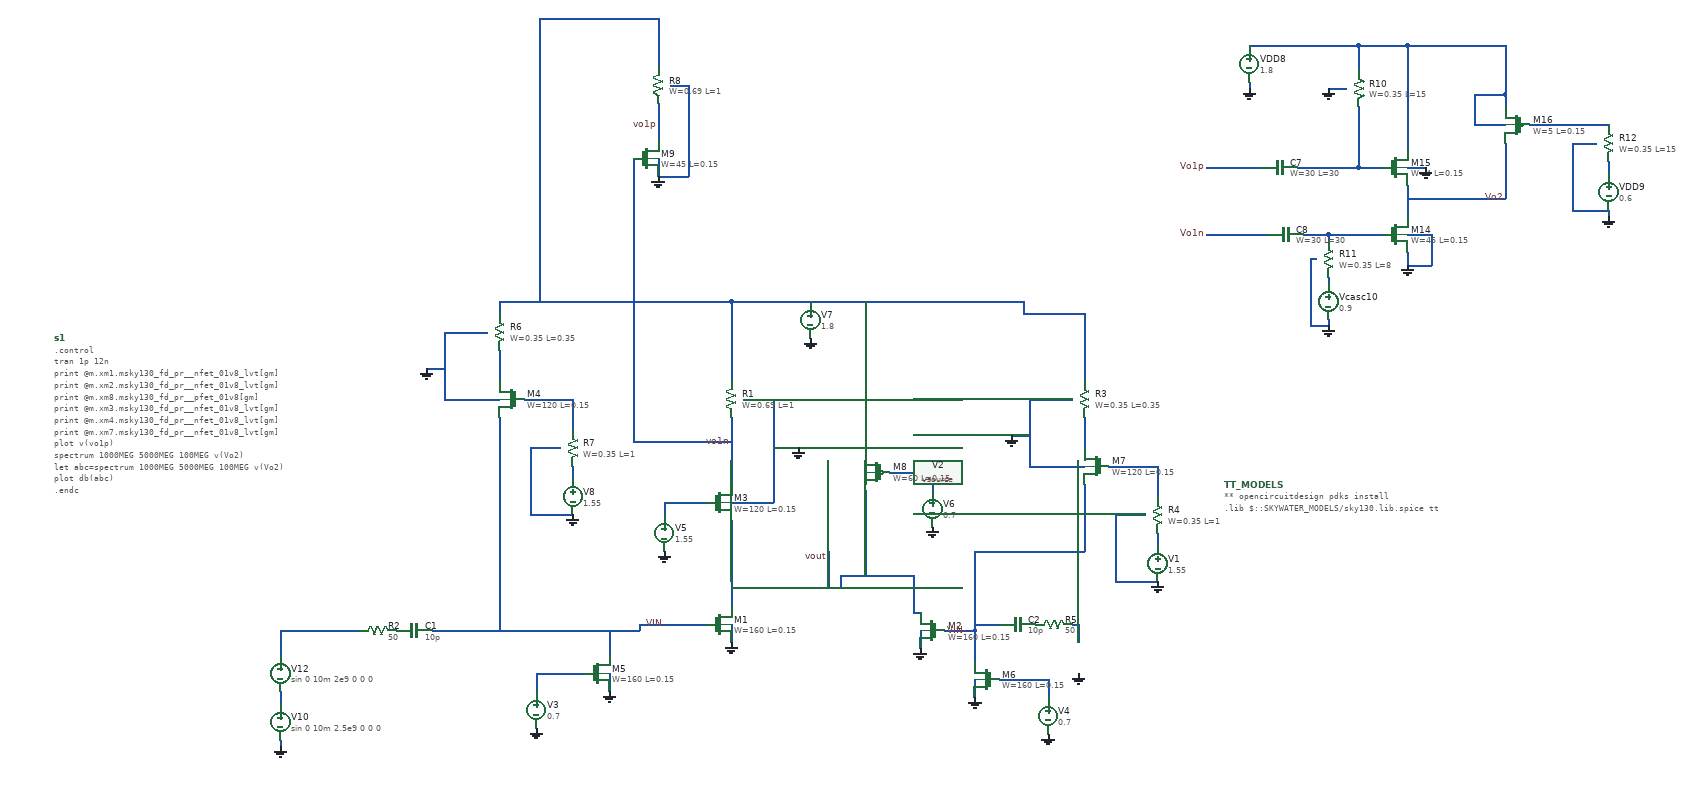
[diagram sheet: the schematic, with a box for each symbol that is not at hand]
v {xschem version=3.0.0 file_version=1.2 }
G {}
K {}
V {}
S {}
E {}
N 90 -90 90 -40 {
lab=vout}
N 390 -90 390 -30 {
lab=vout}
N 390 -30 400 -30 {
lab=vout}
N -10 -10 50 -10 {
lab=VIN}
N 490 0 490 20 {
lab=VIN-}
N 440 -0 490 0 {
lab=VIN-}
N -60 -10 -10 -10 {
lab=VIN}
N 490 -10 530 -10 {
lab=VIN-}
N 490 -10 490 0 {
lab=VIN-}
N -650 0 -650 40 {
lab=#net1}
N 660 -10 660 20 {
lab=#net2}
N -230 70 -230 100 {
lab=#net3}
N 400 0 400 30 {
lab=GND}
N 90 -10 90 20 {
lab=GND}
N 270 -90 390 -90 {
lab=vout}
N 270 -90 270 -70 {
lab=vout}
N 90 -70 270 -70 {
lab=vout}
N -650 100 -650 120 {
lab=#net4}
N -650 180 -650 190 {
lab=GND}
N -650 0 -520 0 {
lab=#net1}
N 250 -130 250 -70 {
lab=vout}
N 650 -10 660 -10 {
lab=#net2}
N 90 -180 90 -80 {
lab=vout}
N -20 -210 50 -210 {
lab=#net5}
N -20 -210 -20 -190 {
lab=#net5}
N 110 -380 160 -380 {
lab=GND}
N 160 -380 160 -220 {
lab=GND}
N 160 -220 160 -210 {
lab=GND}
N 90 -210 160 -210 {
lab=GND}
N 90 -350 90 -240 {
lab=vo1n}
N 90 -540 220 -540 {
lab=#net6}
N 90 -540 90 -410 {
lab=#net6}
N 160 -300 200 -300 {
lab=GND}
N -400 0 -60 0 {
lab=VIN}
N -60 -10 -60 0 {
lab=VIN}
N -290 -350 -290 0 {
lab=VIN}
N -290 -540 90 -540 {
lab=#net6}
N -290 -540 -290 -520 {
lab=#net6}
N -290 -460 -290 -400 {
lab=#net7}
N -380 -490 -310 -490 {
lab=GND}
N -380 -490 -380 -380 {
lab=GND}
N -380 -380 -290 -380 {
lab=GND}
N -410 -430 -380 -430 {
lab=GND}
N -170 -270 -170 -250 {
lab=#net8}
N -170 -380 -170 -330 {
lab=#net9}
N -250 -380 -170 -380 {
lab=#net9}
N -240 -300 -190 -300 {
lab=GND}
N -240 -300 -240 -190 {
lab=GND}
N -240 -190 -170 -190 {
lab=GND}
N -230 70 -150 70 {
lab=#net3}
N -110 10 -110 40 {
lab=VIN}
N -110 0 -110 20 {
lab=VIN}
N -110 70 -110 100 {
lab=GND}
N 610 80 610 110 {
lab=#net10}
N 530 80 610 80 {
lab=#net10}
N 490 80 490 110 {
lab=GND}
N 490 20 490 50 {
lab=VIN-}
N 220 -540 490 -540 {
lab=#net6}
N 310 -230 310 -90 {
lab=vout}
N 310 -530 310 -290 {
lab=#net6}
N 310 -540 310 -530 {
lab=#net6}
N 310 -290 310 -260 {
lab=#net6}
N 420 -260 420 -230 {
lab=#net11}
N 350 -260 420 -260 {
lab=#net11}
N -70 -310 90 -310 {
lab=vo1n}
N -70 -415 -70 -310 {
lab=vo1n}
N -70 -775 -70 -475 {
lab=vo1n}
N -10 -895 20 -895 {
lab=GND}
N 20 -895 20 -755 {
lab=GND}
N 20 -755 20 -745 {
lab=GND}
N -30 -745 20 -745 {
lab=GND}
N -30 -865 -30 -805 {
lab=vo1p}
N -30 -1005 -30 -925 {
lab=#net6}
N -30 -775 -30 -745 {
lab=GND}
N -225 -1000 -225 -540 {
lab=#net6}
N -225 -1005 -30 -1005 {
lab=#net6}
N -225 -1005 -225 -995 {
lab=#net6}
N -70 -480 -70 -410 {
lab=vo1n}
N 670 -430 670 -410 {
lab=#net6}
N 670 -350 670 -290 {
lab=#net12}
N 580 -380 650 -380 {
lab=GND}
N 580 -380 580 -270 {
lab=GND}
N 580 -270 670 -270 {
lab=GND}
N 550 -320 580 -320 {
lab=GND}
N 790 -160 790 -140 {
lab=#net13}
N 790 -270 790 -220 {
lab=#net14}
N 710 -270 790 -270 {
lab=#net14}
N 720 -190 770 -190 {
lab=GND}
N 720 -190 720 -80 {
lab=GND}
N 720 -80 790 -80 {
lab=GND}
N 670 -520 670 -430 {
lab=#net6}
N 670 -240 670 -130 {
lab=VIN-}
N 490 -130 670 -130 {
lab=VIN-}
N 490 -130 490 0 {
lab=VIN-}
N 490 -540 570 -540 {
lab=#net6}
N 570 -540 570 -520 {
lab=#net6}
N 570 -520 670 -520 {
lab=#net6}
N 1070 -890 1100 -890 { lab=GND}
N 1120 -760 1160 -760 { lab=#net15}
N 1120 -860 1120 -760 { lab=#net15}
N 1200 -960 1200 -790 { lab=#net16}
N 1120 -960 1200 -960 { lab=#net16}
N 1120 -960 1120 -920 { lab=#net16}
N 1200 -730 1200 -680 { lab=Vo2}
N 1200 -760 1230 -760 { lab=GND}
N 1360 -800 1360 -710 { lab=Vo2}
N 1200 -710 1360 -710 { lab=Vo2}
N 1310 -830 1360 -830 { lab=#net16}
N 1310 -880 1310 -830 { lab=#net16}
N 1310 -880 1360 -880 { lab=#net16}
N 1360 -880 1360 -860 { lab=#net16}
N 1360 -960 1360 -880 { lab=#net16}
N 1200 -960 1360 -960 { lab=#net16}
N 1400 -830 1430 -830 { lab=#net17}
N 940 -900 940 -890 { lab=GND}
N 940 -960 1120 -960 { lab=#net16}
N 1530 -690 1530 -680 { lab=GND}
N 1420 -830 1470 -830 { lab=#net17}
N 1200 -650 1240 -650 { lab=GND}
N 1240 -650 1240 -600 { lab=GND}
N 1200 -600 1240 -600 { lab=GND}
N 1200 -620 1200 -600 { lab=GND}
N 1020 -760 1120 -760 { lab=#net15}
N 870 -760 960 -760 { lab=Vo1p}
N 1070 -510 1070 -500 { lab=GND}
N 1070 -580 1070 -570 { lab=#net18}
N 1040 -610 1050 -610 { lab=GND}
N 1040 -610 1040 -500 { lab=GND}
N 1040 -500 1070 -500 { lab=GND}
N 1070 -650 1070 -640 { lab=#net19}
N 1070 -650 1160 -650 { lab=#net19}
N 1030 -650 1070 -650 { lab=#net19}
N 870 -650 970 -650 { lab=Vo1n}
N 1470 -830 1530 -830 { lab=#net17}
N 1530 -770 1530 -750 { lab=#net20}
N 1470 -800 1510 -800 { lab=GND}
N 1470 -800 1470 -700 { lab=GND}
N 1470 -700 1470 -690 { lab=GND}
N 1470 -690 1530 -690 { lab=GND}
C {sky130_fd_pr/nfet_01v8_lvt.sym} 70 -10 0 0 {name=M1
L=0.15
W=160
nf=20
mult=1
ad="'int((nf+1)/2) * W/nf * 0.29'" 
pd="'2*int((nf+1)/2) * (W/nf + 0.29)'"
as="'int((nf+2)/2) * W/nf * 0.29'" 
ps="'2*int((nf+2)/2) * (W/nf + 0.29)'"
nrd="'0.29 / W'" nrs="'0.29 / W'"
sa=0 sb=0 sd=0
model=nfet_01v8_lvt
spiceprefix=X
}
C {sky130_fd_pr/nfet_01v8_lvt.sym} 420 0 0 1 {name=M2
L=0.15
W=160
nf=20
mult=1
ad="'int((nf+1)/2) * W/nf * 0.29'" 
pd="'2*int((nf+1)/2) * (W/nf + 0.29)'"
as="'int((nf+2)/2) * W/nf * 0.29'" 
ps="'2*int((nf+2)/2) * (W/nf + 0.29)'"
nrd="'0.29 / W'" nrs="'0.29 / W'"
sa=0 sb=0 sd=0
model=nfet_01v8_lvt
spiceprefix=X
}
C {devices/capa.sym} -430 0 3 0 {name=C1
m=1
value=10p
footprint=1206
device="ceramic capacitor"}
C {devices/capa.sym} 560 -10 1 0 {name=C2
m=1
value=10p
footprint=1206
device="ceramic capacitor"}
C {devices/vsource.sym} 660 40 0 0 {name=V2 value="sin 0 10m 2.5e9 0 0 180"}
C {devices/gnd.sym} 90 20 0 0 {name=l2 lab=GND}
C {devices/gnd.sym} 400 30 0 0 {name=l3 lab=GND}
C {devices/gnd.sym} 660 70 0 0 {name=l4 lab=GND}
C {devices/vsource.sym} -230 130 0 0 {name=V3 value=0.7}
C {devices/gnd.sym} -230 160 0 0 {name=l6 lab=GND}
C {devices/lab_wire.sym} 250 -120 0 0 {name=l10 sig_type=std_logic lab=vout}
C {devices/code.sym} 900 -240 0 0 {name=TT_MODELS
only_toplevel=true
format="tcleval( @value )"
value="
** opencircuitdesign pdks install
.lib $::SKYWATER_MODELS/sky130.lib.spice tt

"
spice_ignore=false}
C {devices/code_shown.sym} -1020 -480 0 0 {name=s1 only_toplevel=false value="
.control
tran 1p 12n
print @m.xm1.msky130_fd_pr__nfet_01v8_lvt[gm]
print @m.xm2.msky130_fd_pr__nfet_01v8_lvt[gm]
print @m.xm8.msky130_fd_pr__pfet_01v8[gm]
print @m.xm3.msky130_fd_pr__nfet_01v8_lvt[gm]
print @m.xm4.msky130_fd_pr__nfet_01v8_lvt[gm]
print @m.xm7.msky130_fd_pr__nfet_01v8_lvt[gm]

plot v(vo1p)
spectrum 1000MEG 5000MEG 100MEG v(Vo2)
let abc=spectrum 1000MEG 5000MEG 100MEG v(Vo2)
plot db(abc)
.endc
"}
C {devices/lab_wire.sym} 480 0 0 0 {name=l9 sig_type=std_logic lab=VIN-}
C {devices/gnd.sym} -650 190 0 0 {name=l1 lab=GND}
C {devices/res.sym} -490 0 3 0 {name=R2
value=50
footprint=1206
device=resistor
m=1}
C {devices/res.sym} 620 -10 3 0 {name=R5
value=50
footprint=1206
device=resistor
m=1}
C {sky130_fd_pr/nfet_01v8_lvt.sym} 70 -210 0 0 {name=M3
L=0.15
W=120
nf=20
mult=1
ad="'int((nf+1)/2) * W/nf * 0.29'" 
pd="'2*int((nf+1)/2) * (W/nf + 0.29)'"
as="'int((nf+2)/2) * W/nf * 0.29'" 
ps="'2*int((nf+2)/2) * (W/nf + 0.29)'"
nrd="'0.29 / W'" nrs="'0.29 / W'"
sa=0 sb=0 sd=0
model=nfet_01v8_lvt
spiceprefix=X
}
C {devices/vsource.sym} -20 -160 0 0 {name=V5 value=1.55}
C {devices/gnd.sym} -20 -130 0 0 {name=l7 lab=GND}
C {sky130_fd_pr/res_high_po_0p69.sym} 90 -380 0 1 {name=R1
W=0.69
L=1
model=res_high_po_0p69
spiceprefix=X
mult=12}
C {devices/vsource.sym} 220 -510 0 0 {name=V7 value=1.8}
C {devices/gnd.sym} 220 -480 0 0 {name=l11 lab=GND}
C {devices/gnd.sym} 200 -300 0 0 {name=l12 lab=GND}
C {devices/lab_wire.sym} 90 -310 0 0 {name=l13 sig_type=std_logic lab=vo1n}
C {sky130_fd_pr/nfet_01v8_lvt.sym} -270 -380 0 1 {name=M4
L=0.15
W=120
nf=10
mult=1
ad="'int((nf+1)/2) * W/nf * 0.29'" 
pd="'2*int((nf+1)/2) * (W/nf + 0.29)'"
as="'int((nf+2)/2) * W/nf * 0.29'" 
ps="'2*int((nf+2)/2) * (W/nf + 0.29)'"
nrd="'0.29 / W'" nrs="'0.29 / W'"
sa=0 sb=0 sd=0
model=nfet_01v8_lvt
spiceprefix=X
}
C {sky130_fd_pr/res_high_po_0p35.sym} -290 -490 0 0 {name=R6
W=0.35
L=0.35
model=res_high_po_0p35
spiceprefix=X
mult=12}
C {devices/gnd.sym} -410 -430 0 0 {name=l14 lab=GND}
C {devices/vsource.sym} -170 -220 0 0 {name=V8 value=1.55}
C {devices/gnd.sym} -170 -190 0 0 {name=l15 lab=GND}
C {sky130_fd_pr/res_high_po_0p35.sym} -170 -300 0 0 {name=R7
W=0.35
L=1
model=res_high_po_0p35
spiceprefix=X
mult=1}
C {sky130_fd_pr/nfet_01v8_lvt.sym} -130 70 0 0 {name=M5
L=0.15
W=160
nf=20
mult=1
ad="'int((nf+1)/2) * W/nf * 0.29'" 
pd="'2*int((nf+1)/2) * (W/nf + 0.29)'"
as="'int((nf+2)/2) * W/nf * 0.29'" 
ps="'2*int((nf+2)/2) * (W/nf + 0.29)'"
nrd="'0.29 / W'" nrs="'0.29 / W'"
sa=0 sb=0 sd=0
model=nfet_01v8_lvt
spiceprefix=X
}
C {devices/gnd.sym} -110 100 0 0 {name=l16 lab=GND}
C {devices/vsource.sym} 610 140 0 1 {name=V4 value=0.7}
C {devices/gnd.sym} 610 170 0 1 {name=l5 lab=GND}
C {sky130_fd_pr/nfet_01v8_lvt.sym} 510 80 0 1 {name=M6
L=0.15
W=160
nf=20
mult=1
ad="'int((nf+1)/2) * W/nf * 0.29'" 
pd="'2*int((nf+1)/2) * (W/nf + 0.29)'"
as="'int((nf+2)/2) * W/nf * 0.29'" 
ps="'2*int((nf+2)/2) * (W/nf + 0.29)'"
nrd="'0.29 / W'" nrs="'0.29 / W'"
sa=0 sb=0 sd=0
model=nfet_01v8_lvt
spiceprefix=X
}
C {devices/gnd.sym} 490 110 0 1 {name=l17 lab=GND}
C {devices/lab_wire.sym} -20 -10 0 0 {name=l20 sig_type=std_logic lab=VIN}
C {sky130_fd_pr/pfet_01v8.sym} 330 -260 0 1 {name=M8
L=0.15
W=60
nf=10
mult=1
ad="'int((nf+1)/2) * W/nf * 0.29'" 
pd="'2*int((nf+1)/2) * (W/nf + 0.29)'"
as="'int((nf+2)/2) * W/nf * 0.29'" 
ps="'2*int((nf+2)/2) * (W/nf + 0.29)'"
nrd="'0.29 / W'" nrs="'0.29 / W'"
sa=0 sb=0 sd=0
model=pfet_01v8
spiceprefix=X
}
C {devices/vsource.sym} 420 -200 0 1 {name=V6 value=0.7}
C {devices/gnd.sym} 420 -170 0 1 {name=l8 lab=GND}
C {devices/vsource.sym} -650 150 0 0 {name=V10 value="sin 0 10m 2.5e9 0 0 0"}
C {sky130_fd_pr/nfet_01v8_lvt.sym} -50 -775 0 0 {name=M9
L=0.15
W=45
nf=8
mult=1
ad="'int((nf+1)/2) * W/nf * 0.29'" 
pd="'2*int((nf+1)/2) * (W/nf + 0.29)'"
as="'int((nf+2)/2) * W/nf * 0.29'" 
ps="'2*int((nf+2)/2) * (W/nf + 0.29)'"
nrd="'0.29 / W'" nrs="'0.29 / W'"
sa=0 sb=0 sd=0
model=nfet_01v8_lvt
spiceprefix=X
}
C {devices/gnd.sym} -30 -745 0 0 {name=l21 lab=GND}
C {devices/lab_wire.sym} -30 -830 0 0 {name=l22 sig_type=std_logic lab=vo1p}
C {sky130_fd_pr/res_high_po_0p69.sym} -30 -895 0 1 {name=R8
W=0.69
L=1
model=res_high_po_0p69
spiceprefix=X
mult=8}
C {sky130_fd_pr/nfet_01v8_lvt.sym} 690 -270 0 1 {name=M7
L=0.15
W=120
nf=10
mult=1
ad="'int((nf+1)/2) * W/nf * 0.29'" 
pd="'2*int((nf+1)/2) * (W/nf + 0.29)'"
as="'int((nf+2)/2) * W/nf * 0.29'" 
ps="'2*int((nf+2)/2) * (W/nf + 0.29)'"
nrd="'0.29 / W'" nrs="'0.29 / W'"
sa=0 sb=0 sd=0
model=nfet_01v8_lvt
spiceprefix=X
}
C {sky130_fd_pr/res_high_po_0p35.sym} 670 -380 0 0 {name=R3
W=0.35
L=0.35
model=res_high_po_0p35
spiceprefix=X
mult=12}
C {devices/gnd.sym} 550 -320 0 0 {name=l18 lab=GND}
C {devices/vsource.sym} 790 -110 0 0 {name=V1 value=1.55}
C {devices/gnd.sym} 790 -80 0 0 {name=l19 lab=GND}
C {sky130_fd_pr/res_high_po_0p35.sym} 790 -190 0 0 {name=R4
W=0.35
L=1
model=res_high_po_0p35
spiceprefix=X
mult=1}
C {devices/vsource.sym} -650 70 0 0 {name=V12 value="sin 0 10m 2e9 0 0 0"}
C {sky130_fd_pr/nfet_01v8_lvt.sym} 1180 -650 0 0 {name=M14
L=0.15
W=45
nf=9
mult=1
ad="'int((nf+1)/2) * W/nf * 0.29'" 
pd="'2*int((nf+1)/2) * (W/nf + 0.29)'"
as="'int((nf+2)/2) * W/nf * 0.29'" 
ps="'2*int((nf+2)/2) * (W/nf + 0.29)'"
nrd="'0.29 / W'" nrs="'0.29 / W'"
sa=0 sb=0 sd=0
model=nfet_01v8_lvt
spiceprefix=X
}
C {sky130_fd_pr/nfet_01v8_lvt.sym} 1180 -760 0 0 {name=M15
L=0.15
W=4
nf=1
mult=3
ad="'int((nf+1)/2) * W/nf * 0.29'" 
pd="'2*int((nf+1)/2) * (W/nf + 0.29)'"
as="'int((nf+2)/2) * W/nf * 0.29'" 
ps="'2*int((nf+2)/2) * (W/nf + 0.29)'"
nrd="'0.29 / W'" nrs="'0.29 / W'"
sa=0 sb=0 sd=0
model=nfet_01v8_lvt
spiceprefix=X
}
C {sky130_fd_pr/res_high_po_0p35.sym} 1120 -890 0 0 {name=R10
W=0.35
L=15
model=res_high_po_0p35
spiceprefix=X
mult=1}
C {devices/gnd.sym} 1070 -890 0 0 {name=l36 lab=GND}
C {sky130_fd_pr/pfet_01v8.sym} 1380 -830 0 1 {name=M16
L=0.15
W=5
nf=1
mult=16
ad="'int((nf+1)/2) * W/nf * 0.29'" 
pd="'2*int((nf+1)/2) * (W/nf + 0.29)'"
as="'int((nf+2)/2) * W/nf * 0.29'" 
ps="'2*int((nf+2)/2) * (W/nf + 0.29)'"
nrd="'0.29 / W'" nrs="'0.29 / W'"
sa=0 sb=0 sd=0
model=pfet_01v8
spiceprefix=X
}
C {devices/vsource.sym} 940 -930 0 1 {name=VDD8 value=1.8}
C {devices/gnd.sym} 940 -890 0 1 {name=l37 lab=GND}
C {devices/vsource.sym} 1530 -720 0 1 {name=VDD9 value=0.6}
C {devices/gnd.sym} 1530 -680 0 1 {name=l38 lab=GND}
C {devices/gnd.sym} 1230 -760 0 1 {name=l39 lab=GND}
C {sky130_fd_pr/cap_mim_m3_2.sym} 990 -760 3 0 {name=C7 model=cap_mim_m3_2 W=30 L=30 MF=1 spiceprefix=X}
C {devices/gnd.sym} 1200 -600 0 1 {name=l40 lab=GND}
C {devices/vsource.sym} 1070 -540 0 0 {name=Vcasc10 value=0.9}
C {devices/gnd.sym} 1070 -500 0 0 {name=l41 lab=GND}
C {sky130_fd_pr/res_high_po_0p35.sym} 1070 -610 0 0 {name=R11
W=0.35
L=8
model=res_high_po_0p35
spiceprefix=X
mult=1}
C {sky130_fd_pr/cap_mim_m3_2.sym} 1000 -650 3 0 {name=C8 model=cap_mim_m3_2 W=30 L=30 MF=1 spiceprefix=X}
C {devices/lab_wire.sym} 870 -760 0 0 {name=l42 sig_type=std_logic lab=Vo1p}
C {devices/lab_wire.sym} 870 -650 0 0 {name=l43 sig_type=std_logic lab=Vo1n}
C {sky130_fd_pr/res_high_po_0p35.sym} 1530 -800 0 0 {name=R12
W=0.35
L=15
model=res_high_po_0p35
spiceprefix=X
mult=1}
C {devices/lab_wire.sym} 1360 -710 0 0 {name=l44 sig_type=std_logic lab=Vo2}
